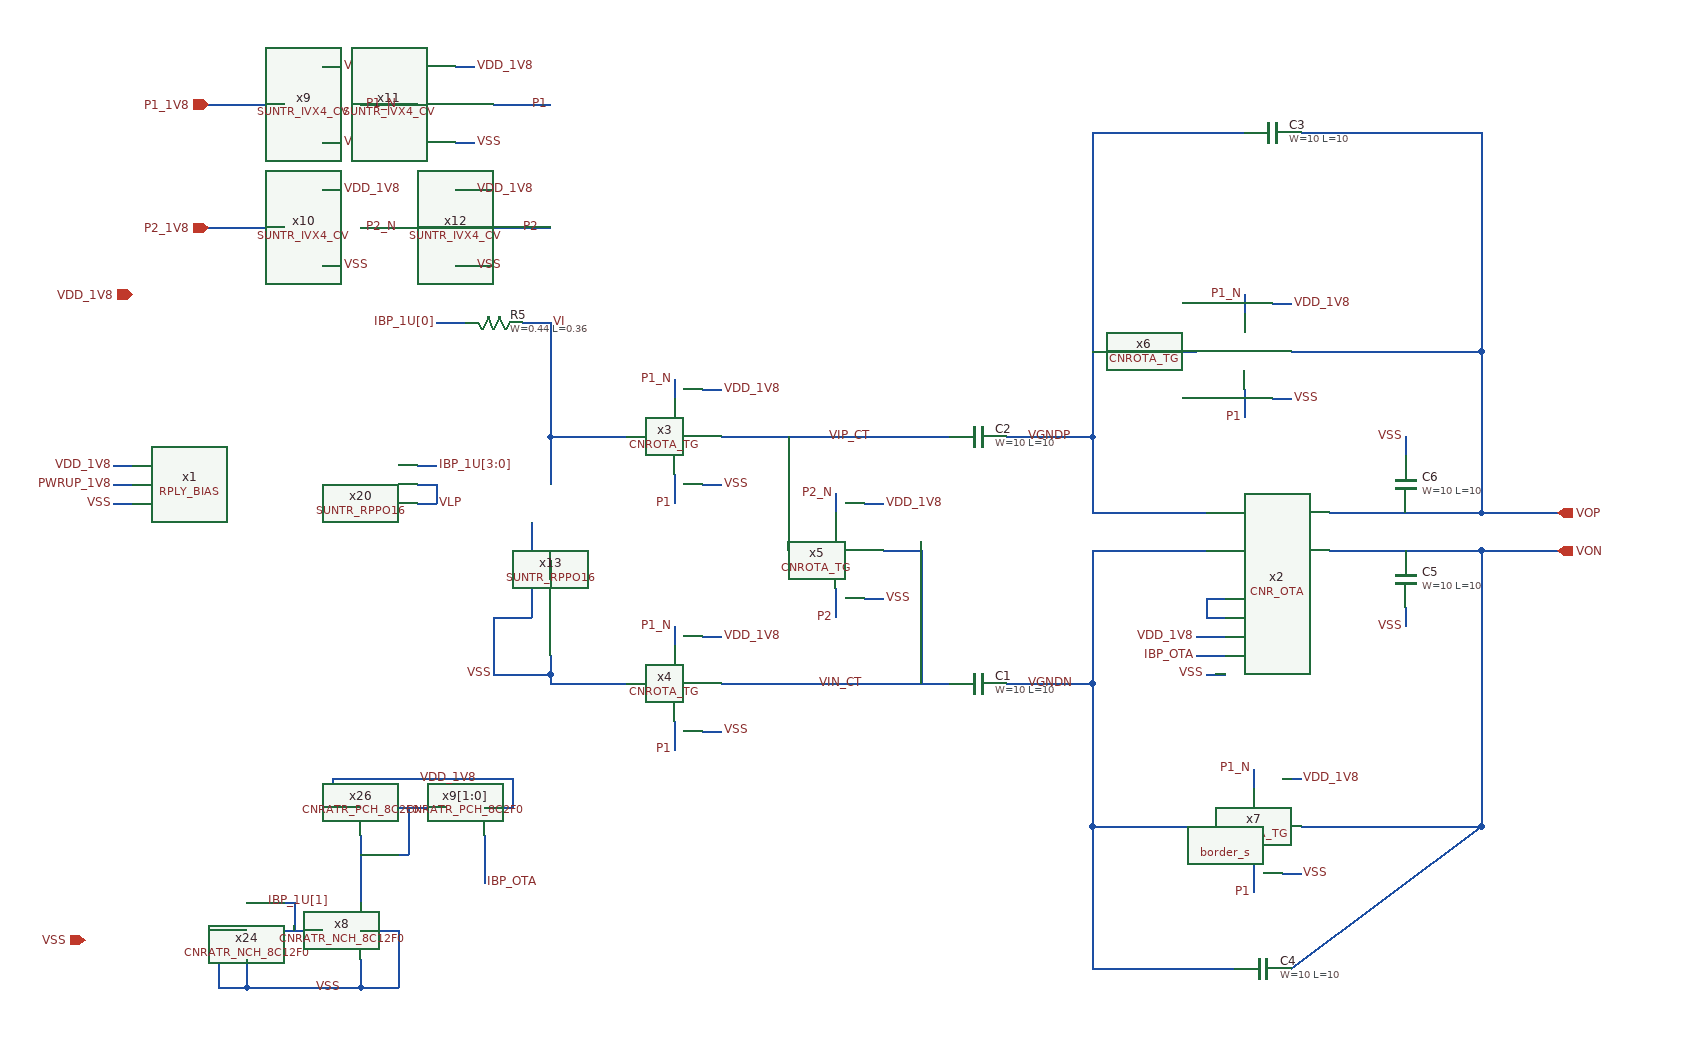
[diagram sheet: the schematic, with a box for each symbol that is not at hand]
v {xschem version=3.4.5 file_version=1.2
}
G {}
K {}
V {}
S {}
E {}
N 160 -480 180 -480 {
lab=VSS}
N 160 -500 180 -500 {
lab=PWRUP_1V8}
N 160 -520 180 -520 {
lab=VDD_1V8}
N 480 -520 500 -520 {
lab=IBP_1U[3:0]}
N 1310 -380 1330 -380 {
lab=#net1}
N 1310 -380 1310 -360 {
lab=#net1}
N 1310 -360 1330 -360 {
lab=#net1}
N 1310 -300 1330 -300 {
lab=VSS}
N 1300 -320 1330 -320 {
lab=IBP_OTA}
N 1300 -340 1330 -340 {
lab=VDD_1V8}
N 780 -600 800 -600 {
lab=VDD_1V8}
N 780 -500 800 -500 {
lab=VSS}
N 750 -510 750 -480 {
lab=P1}
N 750 -610 750 -590 {
lab=P1_N}
N 780 -340 800 -340 {
lab=VDD_1V8}
N 780 -240 800 -240 {
lab=VSS}
N 750 -250 750 -220 {
lab=P1}
N 750 -350 750 -330 {
lab=P1_N}
N 950 -480 970 -480 {
lab=VDD_1V8}
N 950 -380 970 -380 {
lab=VSS}
N 920 -390 920 -360 {
lab=P2}
N 920 -490 920 -470 {
lab=P2_N}
N 800 -550 1040 -550 {
lab=VIP_CT}
N 800 -290 1040 -290 {
lab=VIN_CT}
N 1380 -690 1400 -690 {
lab=VDD_1V8}
N 1380 -590 1400 -590 {
lab=VSS}
N 1350 -600 1350 -570 {
lab=P1}
N 1350 -700 1350 -680 {
lab=P1_N}
N 1390 -190 1410 -190 {
lab=VDD_1V8}
N 1390 -90 1410 -90 {
lab=VSS}
N 1360 -100 1360 -70 {
lab=P1}
N 1360 -200 1360 -180 {
lab=P1_N}
N 1190 -140 1310 -140 {
lab=VGNDN}
N 1190 -290 1190 -140 {
lab=VGNDN}
N 1100 -290 1190 -290 {
lab=VGNDN}
N 1190 -430 1310 -430 {
lab=VGNDN}
N 1190 -430 1190 -290 {
lab=VGNDN}
N 1190 10 1340 10 {
lab=VGNDN}
N 1190 -140 1190 10 {
lab=VGNDN}
N 1440 -430 1600 -430 {
lab=VON}
N 1410 -140 1600 -140 {
lab=VON}
N 1190 -870 1350 -870 {
lab=VGNDP}
N 1190 -870 1190 -550 {
lab=VGNDP}
N 1100 -550 1190 -550 {
lab=VGNDP}
N 1200 -640 1300 -640 {
lab=VGNDP}
N 1190 -470 1310 -470 {
lab=VGNDP}
N 1190 -550 1190 -470 {
lab=VGNDP}
N 1190 -640 1200 -640 {
lab=VGNDP}
N 1400 -640 1600 -640 {
lab=VOP}
N 1600 -640 1600 -470 {
lab=VOP}
N 1440 -470 1600 -470 {
lab=VOP}
N 1600 -870 1600 -640 {
lab=VOP}
N 1410 -870 1600 -870 {
lab=VOP}
N 660 -550 700 -550 {
lab=VI}
N 660 -290 700 -290 {
lab=VSS}
N 1520 -550 1520 -530 {
lab=VSS}
N 1520 -370 1520 -350 {
lab=VSS}
N 420 0 420 30 {
lab=VSS}
N 300 30 420 30 {
lab=VSS}
N 300 0 300 30 {
lab=VSS}
N 270 -30 300 -30 {
lab=VSS}
N 270 -30 270 30 {
lab=VSS}
N 270 30 300 30 {
lab=VSS}
N 420 -30 460 -30 {
lab=VSS}
N 460 -30 460 30 {
lab=VSS}
N 420 30 460 30 {
lab=VSS}
N 340 -30 380 -30 {
lab=IBP_1U[1]}
N 300 -60 350 -60 {
lab=IBP_1U[1]}
N 350 -60 350 -30 {
lab=IBP_1U[1]}
N 420 -130 420 -60 {
lab=#net2}
N 390 -160 420 -160 {
lab=VDD_1V8}
N 390 -190 390 -160 {
lab=VDD_1V8}
N 390 -190 420 -190 {
lab=VDD_1V8}
N 420 -190 550 -190 {
lab=VDD_1V8}
N 550 -160 580 -160 {
lab=VDD_1V8}
N 580 -190 580 -160 {
lab=VDD_1V8}
N 550 -190 580 -190 {
lab=VDD_1V8}
N 460 -160 510 -160 {
lab=#net2}
N 460 -160 470 -160 {
lab=#net2}
N 470 -160 470 -110 {
lab=#net2}
N 420 -110 470 -110 {
lab=#net2}
N 550 -130 550 -80 {
lab=IBP_OTA}
N 560 -300 620 -300 {
lab=VSS}
N 560 -360 560 -300 {
lab=VSS}
N 970 -430 1010 -430 {
lab=VIN_CT}
N 1010 -430 1010 -290 {
lab=VIN_CT}
N 870 -550 870 -430 {
lab=VIP_CT}
N 620 -550 660 -550 {
lab=VI}
N 620 -650 620 -550 {
lab=VI}
N 1600 -430 1680 -430 {
lab=VON}
N 1600 -470 1680 -470 {
lab=VOP}
N 260 -770 340 -770 {
lab=P2_1V8}
N 260 -900 340 -900 {
lab=P1_1V8}
N 380 -940 400 -940 {
lab=VDD_1V8}
N 380 -860 400 -860 {
lab=VSS}
N 380 -730 400 -730 {
lab=VSS}
N 380 -810 400 -810 {
lab=VDD_1V8}
N 520 -940 540 -940 {
lab=VDD_1V8}
N 520 -860 540 -860 {
lab=VSS}
N 420 -900 480 -900 {
lab=P1_N}
N 560 -900 620 -900 {
lab=P1}
N 520 -810 540 -810 {
lab=VDD_1V8}
N 520 -730 540 -730 {
lab=VSS}
N 560 -770 620 -770 {
lab=P2}
N 420 -770 480 -770 {
lab=P2_N}
N 620 -290 660 -290 {
lab=VSS}
N 620 -300 620 -290 {
lab=VSS}
N 620 -550 620 -500 {
lab=VI}
N 560 -360 600 -360 {
lab=VSS}
N 620 -420 620 -400 {
lab=#net3}
N 620 -320 620 -300 {
lab=VSS}
N 600 -460 600 -360 {
lab=VSS}
N 500 -670 530 -670 {
lab=IBP_1U[0]}
N 590 -670 620 -670 {
lab=VI}
N 620 -670 620 -650 {
lab=VI}
N 480 -500 500 -500 {
lab=VDD_1V8}
N 500 -500 500 -480 {
lab=VDD_1V8}
N 480 -480 500 -480 {
lab=VDD_1V8}
N 1400 10 1600 -140 {
lab=VON}
N 1600 -430 1600 -140 {
lab=VON}
C {RPLY_BIAS_SKY130NM/RPLY_BIAS.sym} 330 -500 0 0 {name=x1}
C {devices/ipin.sym} 180 -700 0 0 {name=p1 lab=VDD_1V8}
C {devices/ipin.sym} 130 -20 0 0 {name=p2 lab=VSS}
C {devices/lab_wire.sym} 160 -500 0 0 {name=p16 sig_type=std_logic lab=PWRUP_1V8}
C {devices/lab_wire.sym} 160 -480 0 0 {name=p3 sig_type=std_logic lab=VSS}
C {devices/lab_wire.sym} 160 -520 0 0 {name=p4 sig_type=std_logic lab=VDD_1V8}
C {devices/lab_wire.sym} 500 -520 0 1 {name=p5 sig_type=std_logic lab=IBP_1U[3:0]}
C {devices/lab_wire.sym} 560 -300 0 0 {name=p6 sig_type=std_logic lab=VSS}
C {CNR_OTA_SKY130NM/CNR_OTA.sym} 1440 -440 0 0 {name=x2}
C {devices/lab_wire.sym} 1310 -300 0 0 {name=p8 sig_type=std_logic lab=VSS}
C {devices/lab_wire.sym} 1300 -320 0 0 {name=p9 sig_type=std_logic lab=IBP_OTA}
C {devices/lab_wire.sym} 1300 -340 0 0 {name=p13 sig_type=std_logic lab=VDD_1V8}
C {sky130_fd_pr/cap_mim_m3_1.sym} 1070 -550 1 0 {name=C2 model=cap_mim_m3_1 W=10 L=10 MF=10 spiceprefix=X}
C {TB_CNR_OTA/CNROTA_TG.sym} 700 -550 0 0 {name=x3}
C {devices/lab_wire.sym} 800 -600 0 1 {name=p17 sig_type=std_logic lab=VDD_1V8}
C {devices/lab_wire.sym} 800 -500 0 1 {name=p18 sig_type=std_logic lab=VSS}
C {devices/lab_wire.sym} 750 -480 0 0 {name=p19 sig_type=std_logic lab=P1}
C {devices/lab_wire.sym} 750 -610 0 0 {name=p20 sig_type=std_logic lab=P1_N}
C {sky130_fd_pr/cap_mim_m3_1.sym} 1070 -290 1 0 {name=C1 model=cap_mim_m3_1 W=10 L=10 MF=10 spiceprefix=X}
C {TB_CNR_OTA/CNROTA_TG.sym} 700 -290 0 0 {name=x4}
C {devices/lab_wire.sym} 800 -340 0 1 {name=p21 sig_type=std_logic lab=VDD_1V8}
C {devices/lab_wire.sym} 800 -240 0 1 {name=p22 sig_type=std_logic lab=VSS}
C {devices/lab_wire.sym} 750 -220 0 0 {name=p23 sig_type=std_logic lab=P1}
C {devices/lab_wire.sym} 750 -350 0 0 {name=p24 sig_type=std_logic lab=P1_N}
C {TB_CNR_OTA/CNROTA_TG.sym} 870 -430 0 0 {name=x5}
C {devices/lab_wire.sym} 970 -480 0 1 {name=p25 sig_type=std_logic lab=VDD_1V8}
C {devices/lab_wire.sym} 970 -380 0 1 {name=p26 sig_type=std_logic lab=VSS}
C {devices/lab_wire.sym} 920 -360 0 0 {name=p27 sig_type=std_logic lab=P2}
C {devices/lab_wire.sym} 920 -490 0 0 {name=p28 sig_type=std_logic lab=P2_N}
C {sky130_fd_pr/cap_mim_m3_1.sym} 1380 -870 1 0 {name=C3 model=cap_mim_m3_1 W=10 L=10 MF=2 spiceprefix=X}
C {TB_CNR_OTA/CNROTA_TG.sym} 1300 -640 0 0 {name=x6}
C {devices/lab_wire.sym} 1400 -690 0 1 {name=p29 sig_type=std_logic lab=VDD_1V8}
C {devices/lab_wire.sym} 1400 -590 0 1 {name=p30 sig_type=std_logic lab=VSS}
C {devices/lab_wire.sym} 1350 -570 0 0 {name=p31 sig_type=std_logic lab=P1}
C {devices/lab_wire.sym} 1350 -700 0 0 {name=p32 sig_type=std_logic lab=P1_N}
C {TB_CNR_OTA/CNROTA_TG.sym} 1310 -140 0 0 {name=x7}
C {devices/lab_wire.sym} 1410 -190 0 1 {name=p33 sig_type=std_logic lab=VDD_1V8}
C {devices/lab_wire.sym} 1410 -90 0 1 {name=p34 sig_type=std_logic lab=VSS}
C {devices/lab_wire.sym} 1360 -70 0 0 {name=p35 sig_type=std_logic lab=P1}
C {devices/lab_wire.sym} 1360 -200 0 0 {name=p36 sig_type=std_logic lab=P1_N}
C {sky130_fd_pr/cap_mim_m3_1.sym} 1370 10 1 0 {name=C4 model=cap_mim_m3_1 W=10 L=10 MF=2 spiceprefix=X}
C {sky130_fd_pr/cap_mim_m3_1.sym} 1520 -400 0 0 {name=C5 model=cap_mim_m3_1 W=10 L=10 MF=20 spiceprefix=X}
C {sky130_fd_pr/cap_mim_m3_1.sym} 1520 -500 2 0 {name=C6 model=cap_mim_m3_1 W=10 L=10 MF=20 spiceprefix=X}
C {devices/lab_wire.sym} 1520 -550 1 0 {name=p39 sig_type=std_logic lab=VSS}
C {devices/lab_wire.sym} 1520 -350 3 0 {name=p40 sig_type=std_logic lab=VSS}
C {CNR_ATR_SKY130NM/CNRATR_NCH_8C12F0.sym} 340 -30 0 1 {name=x24 }
C {CNR_ATR_SKY130NM/CNRATR_NCH_8C12F0.sym} 380 -30 0 0 {name=x8 }
C {CNR_ATR_SKY130NM/CNRATR_PCH_8C2F0.sym} 460 -160 0 1 {name=x26 }
C {CNR_ATR_SKY130NM/CNRATR_PCH_8C2F0.sym} 510 -160 0 0 {name=x9[1:0]}
C {devices/lab_wire.sym} 550 -80 0 1 {name=p10 sig_type=std_logic lab=IBP_OTA}
C {devices/lab_wire.sym} 320 -60 0 1 {name=p11 sig_type=std_logic lab=IBP_1U[1]}
C {cborder/border_s.sym} 1300 -90 0 0 {}
C {devices/opin.sym} 1680 -470 0 0 {name=p12 lab=VOP}
C {devices/opin.sym} 1680 -430 0 0 {name=p14 lab=VON}
C {devices/ipin.sym} 260 -900 0 0 {name=p15 lab=P1_1V8}
C {devices/ipin.sym} 260 -770 0 0 {name=p37 lab=P2_1V8}
C {SUN_TR_SKY130NM/SUNTR_IVX4_CV.sym} 340 -900 0 0 {name=x9 }
C {SUN_TR_SKY130NM/SUNTR_IVX4_CV.sym} 340 -770 0 0 {name=x10 }
C {devices/lab_wire.sym} 400 -940 0 1 {name=p38 sig_type=std_logic lab=VDD_1V8}
C {devices/lab_wire.sym} 400 -860 0 1 {name=p41 sig_type=std_logic lab=VSS}
C {devices/lab_wire.sym} 400 -730 0 1 {name=p42 sig_type=std_logic lab=VSS}
C {devices/lab_wire.sym} 400 -810 0 1 {name=p43 sig_type=std_logic lab=VDD_1V8}
C {SUN_TR_SKY130NM/SUNTR_IVX4_CV.sym} 480 -900 0 0 {name=x11 }
C {devices/lab_wire.sym} 540 -940 0 1 {name=p44 sig_type=std_logic lab=VDD_1V8}
C {devices/lab_wire.sym} 540 -860 0 1 {name=p45 sig_type=std_logic lab=VSS}
C {SUN_TR_SKY130NM/SUNTR_IVX4_CV.sym} 480 -770 0 0 {name=x12 }
C {devices/lab_wire.sym} 540 -810 0 1 {name=p46 sig_type=std_logic lab=VDD_1V8}
C {devices/lab_wire.sym} 540 -730 0 1 {name=p47 sig_type=std_logic lab=VSS}
C {devices/lab_wire.sym} 460 -900 0 0 {name=p48 sig_type=std_logic lab=P1_N}
C {devices/lab_wire.sym} 620 -900 0 0 {name=p49 sig_type=std_logic lab=P1}
C {devices/lab_wire.sym} 460 -770 0 0 {name=p50 sig_type=std_logic lab=P2_N}
C {devices/lab_wire.sym} 610 -770 0 0 {name=p51 sig_type=std_logic lab=P2}
C {devices/lab_wire.sym} 480 -190 0 1 {name=p52 sig_type=std_logic lab=VDD_1V8}
C {devices/lab_wire.sym} 370 30 0 1 {name=p53 sig_type=std_logic lab=VSS}
C {devices/lab_wire.sym} 910 -550 0 1 {name=p54 sig_type=std_logic lab=VIP_CT}
C {devices/lab_wire.sym} 900 -290 0 1 {name=p55 sig_type=std_logic lab=VIN_CT}
C {devices/lab_wire.sym} 1120 -550 0 1 {name=p56 sig_type=std_logic lab=VGNDP}
C {devices/lab_wire.sym} 1120 -290 0 1 {name=p57 sig_type=std_logic lab=VGNDN}
C {SUN_TR_SKY130NM/SUNTR_RPPO16.sym} 620 -500 1 0 {name=x20 }
C {SUN_TR_SKY130NM/SUNTR_RPPO16.sym} 620 -400 1 0 {name=x13 }
C {sky130_fd_pr/res_generic_m3.sym} 560 -670 1 0 {name=R5
W=0.44
L=0.36
model=res_generic_m3
mult=1}
C {devices/lab_wire.sym} 500 -670 0 0 {name=p7 sig_type=std_logic lab=IBP_1U[0]}
C {devices/lab_wire.sym} 620 -670 0 1 {name=p58 sig_type=std_logic lab=VI}
C {devices/lab_wire.sym} 500 -480 0 1 {name=p59 sig_type=std_logic lab=VLP}
